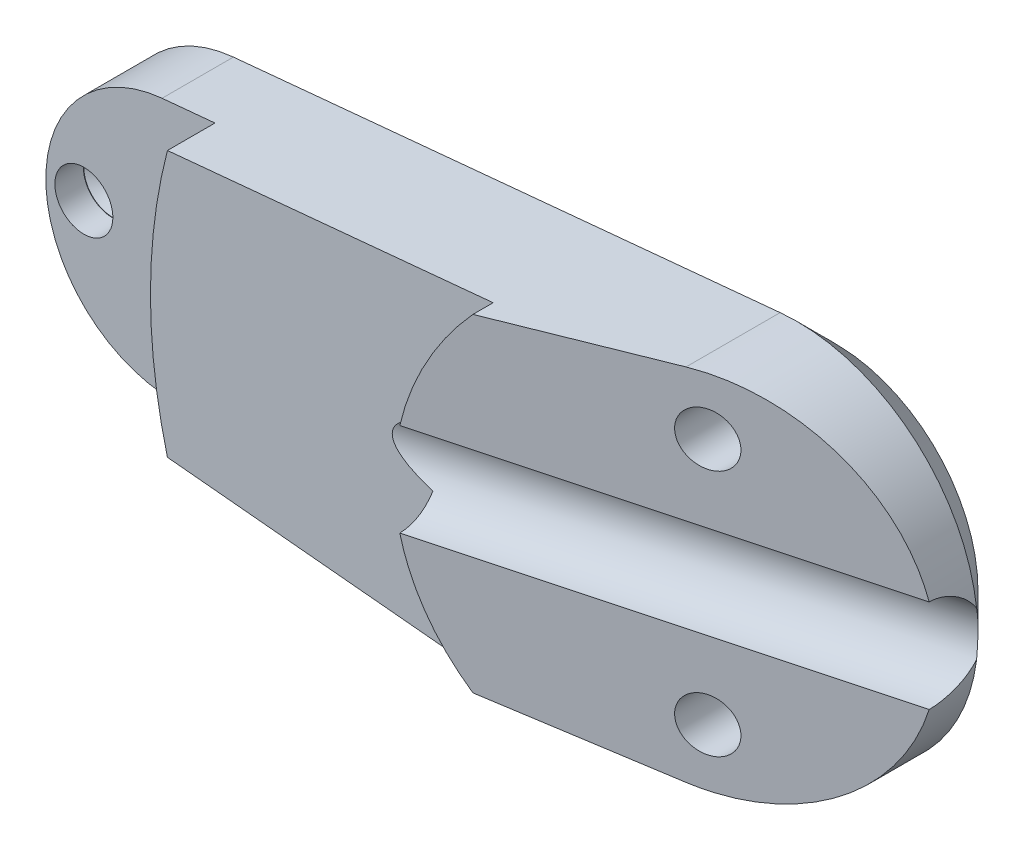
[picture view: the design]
ISO-10303-21;
HEADER;
FILE_DESCRIPTION(('STEP AP214'),'2;1');
FILE_NAME('part.step','',(''),(''),'','','');
FILE_SCHEMA(('AUTOMOTIVE_DESIGN { 1 0 10303 214 1 1 1 1 }'));
ENDSEC;
DATA;
#1=APPLICATION_CONTEXT('core data for automotive mechanical design processes');
#2=APPLICATION_PROTOCOL_DEFINITION('international standard','automotive_design',2000,#1);
#3=PRODUCT_CONTEXT('',#1,'mechanical');
#4=PRODUCT('Part','Part','',(#3));
#5=PRODUCT_RELATED_PRODUCT_CATEGORY('part','',(#4));
#6=PRODUCT_DEFINITION_FORMATION('','',#4);
#7=PRODUCT_DEFINITION_CONTEXT('part definition',#1,'design');
#8=PRODUCT_DEFINITION('design','',#6,#7);
#9=PRODUCT_DEFINITION_SHAPE('','',#8);
#10=(LENGTH_UNIT() NAMED_UNIT(*) SI_UNIT(.MILLI.,.METRE.));
#11=(NAMED_UNIT(*) PLANE_ANGLE_UNIT() SI_UNIT($,.RADIAN.));
#12=(NAMED_UNIT(*) SI_UNIT($,.STERADIAN.) SOLID_ANGLE_UNIT());
#13=UNCERTAINTY_MEASURE_WITH_UNIT(LENGTH_MEASURE(1.E-05),#10,'distance_accuracy_value','');
#14=(GEOMETRIC_REPRESENTATION_CONTEXT(3) GLOBAL_UNCERTAINTY_ASSIGNED_CONTEXT((#13)) GLOBAL_UNIT_ASSIGNED_CONTEXT((#10,
#11,#12)) REPRESENTATION_CONTEXT('',''));
#15=CARTESIAN_POINT('',(0.,0.,0.));
#16=DIRECTION('',(0.,0.,1.));
#17=DIRECTION('',(1.,0.,0.));
#18=AXIS2_PLACEMENT_3D('',#15,#16,#17);
#19=CARTESIAN_POINT('',(-19.,-25.,18.5));
#20=DIRECTION('',(-0.258819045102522,0.,-0.965925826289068));
#21=DIRECTION('',(-0.965925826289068,0.,0.258819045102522));
#22=AXIS2_PLACEMENT_3D('',#19,#20,#21);
#23=PLANE('',#22);
#24=CARTESIAN_POINT('',(0.,-13.,13.4089653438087));
#25=DIRECTION('',(-0.258819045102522,0.,-0.965925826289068));
#26=DIRECTION('',(0.965925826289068,0.,-0.258819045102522));
#27=AXIS2_PLACEMENT_3D('',#24,#25,#26);
#28=ELLIPSE('',#27,2.84700949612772,2.74999999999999);
#29=CARTESIAN_POINT('',(2.74999999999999,-13.,12.6721050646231));
#30=VERTEX_POINT('',#29);
#31=EDGE_CURVE('E214',#30,#30,#28,.T.);
#32=ORIENTED_EDGE('',*,*,#31,.T.);
#33=EDGE_LOOP('',(#32));
#34=FACE_BOUND('',#33,.T.);
#35=DIRECTION('',(-0.965925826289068,0.,0.258819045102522));
#36=VECTOR('',#35,1.);
#37=CARTESIAN_POINT('',(-66.9752612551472,-4.89897948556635,31.3549325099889));
#38=LINE('',#37,#36);
#39=CARTESIAN_POINT('',(-25.5342906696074,-4.89897948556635,20.2508579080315));
#40=VERTEX_POINT('',#39);
#41=CARTESIAN_POINT('',(18.3575597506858,-4.89897948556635,8.49007203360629));
#42=VERTEX_POINT('',#41);
#43=EDGE_CURVE('E230',#40,#42,#38,.F.);
#44=ORIENTED_EDGE('',*,*,#43,.F.);
#45=CARTESIAN_POINT('',(0.,0.,13.4089653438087));
#46=DIRECTION('',(-0.258819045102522,0.,-0.965925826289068));
#47=DIRECTION('',(0.965925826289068,0.,-0.258819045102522));
#48=AXIS2_PLACEMENT_3D('',#45,#46,#47);
#49=ELLIPSE('',#48,26.9171806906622,26.);
#50=CARTESIAN_POINT('',(-19.4699847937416,-17.231357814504,18.625932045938));
#51=VERTEX_POINT('',#50);
#52=EDGE_CURVE('E186',#40,#51,#49,.F.);
#53=ORIENTED_EDGE('',*,*,#52,.T.);
#54=DIRECTION('',(0.961862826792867,-0.0916240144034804,-0.257730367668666));
#55=VECTOR('',#54,1.);
#56=CARTESIAN_POINT('',(-10.7530083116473,-18.0617094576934,16.2902252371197));
#57=LINE('',#56,#55);
#58=CARTESIAN_POINT('',(-1.80172413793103,-18.9143805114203,13.8917358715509));
#59=VERTEX_POINT('',#58);
#60=EDGE_CURVE('E225',#51,#59,#57,.T.);
#61=ORIENTED_EDGE('',*,*,#60,.T.);
#62=CARTESIAN_POINT('',(0.,0.,13.4089653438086));
#63=DIRECTION('',(-0.258819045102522,0.,-0.965925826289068));
#64=DIRECTION('',(0.965925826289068,0.,-0.258819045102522));
#65=AXIS2_PLACEMENT_3D('',#62,#63,#64);
#66=ELLIPSE('',#65,19.6702474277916,19.);
#67=EDGE_CURVE('E375',#42,#59,#66,.T.);
#68=ORIENTED_EDGE('',*,*,#67,.F.);
#69=EDGE_LOOP('',(#44,#53,#61,#68));
#70=FACE_BOUND('',#69,.T.);
#71=ADVANCED_FACE('F38',(#34,#70),#23,.F.);
#72=CARTESIAN_POINT('',(0.,0.,18.5));
#73=DIRECTION('',(0.,0.,-1.));
#74=DIRECTION('',(-1.,0.,0.));
#75=AXIS2_PLACEMENT_3D('',#72,#73,#74);
#76=CYLINDRICAL_SURFACE('',#75,19.);
#77=DIRECTION('',(0.,0.,-1.));
#78=VECTOR('',#77,1.);
#79=CARTESIAN_POINT('',(-1.80172413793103,-18.9143805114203,50.));
#80=LINE('',#79,#78);
#81=CARTESIAN_POINT('',(-1.80172413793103,-18.9143805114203,4.));
#82=VERTEX_POINT('',#81);
#83=EDGE_CURVE('E240',#59,#82,#80,.T.);
#84=ORIENTED_EDGE('',*,*,#83,.T.);
#85=CARTESIAN_POINT('',(0.,0.,4.));
#86=DIRECTION('',(0.,0.,1.));
#87=DIRECTION('',(1.,0.,0.));
#88=AXIS2_PLACEMENT_3D('',#85,#86,#87);
#89=CIRCLE('',#88,19.);
#90=CARTESIAN_POINT('',(18.8560184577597,-2.33464513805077,3.99999999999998));
#91=VERTEX_POINT('',#90);
#92=EDGE_CURVE('E267',#82,#91,#89,.T.);
#93=ORIENTED_EDGE('',*,*,#92,.T.);
#94=CARTESIAN_POINT('',(19.,0.,13.4943115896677));
#95=CARTESIAN_POINT('',(18.9999933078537,-0.275202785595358,13.4943010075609));
#96=CARTESIAN_POINT('',(18.9939621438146,-0.550519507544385,13.4718550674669));
#97=CARTESIAN_POINT('',(18.9704599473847,-1.09345599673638,13.3825276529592));
#98=CARTESIAN_POINT('',(18.9529820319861,-1.36107103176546,13.3156194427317));
#99=CARTESIAN_POINT('',(18.9084732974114,-1.8808728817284,13.1388946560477));
#100=CARTESIAN_POINT('',(18.8814438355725,-2.13306188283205,13.0290841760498));
#101=CARTESIAN_POINT('',(18.820780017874,-2.6148130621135,12.7691257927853));
#102=CARTESIAN_POINT('',(18.7871464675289,-2.84437799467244,12.618982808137));
#103=CARTESIAN_POINT('',(18.717105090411,-3.27371933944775,12.2824751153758));
#104=CARTESIAN_POINT('',(18.6807051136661,-3.47357561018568,12.0962107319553));
#105=CARTESIAN_POINT('',(18.6091595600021,-3.8384687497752,11.6920348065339));
#106=CARTESIAN_POINT('',(18.5740138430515,-4.0035095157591,11.4741268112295));
#107=CARTESIAN_POINT('',(18.5093664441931,-4.29244776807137,11.0154345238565));
#108=CARTESIAN_POINT('',(18.4798034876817,-4.41680442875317,10.7749480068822));
#109=CARTESIAN_POINT('',(18.4290663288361,-4.62395487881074,10.275907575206));
#110=CARTESIAN_POINT('',(18.4078915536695,-4.70675150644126,10.0173548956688));
#111=CARTESIAN_POINT('',(18.3761291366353,-4.82927605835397,9.4903227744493));
#112=CARTESIAN_POINT('',(18.3655162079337,-4.8691068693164,9.22186864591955));
#113=CARTESIAN_POINT('',(18.3556109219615,-4.90631242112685,8.68186067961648));
#114=CARTESIAN_POINT('',(18.3563206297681,-4.90367941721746,8.41030628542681));
#115=CARTESIAN_POINT('',(18.368851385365,-4.85653271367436,7.86083197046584));
#116=CARTESIAN_POINT('',(18.3810907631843,-4.81044219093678,7.58305859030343));
#117=CARTESIAN_POINT('',(18.4156182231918,-4.67650714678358,7.03840657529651));
#118=CARTESIAN_POINT('',(18.4379098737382,-4.58864779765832,6.77153184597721));
#119=CARTESIAN_POINT('',(18.4917817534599,-4.36668197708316,6.23751517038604));
#120=CARTESIAN_POINT('',(18.5238833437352,-4.22987630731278,5.97154822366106));
#121=CARTESIAN_POINT('',(18.5929983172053,-3.91488247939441,5.46570565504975));
#122=CARTESIAN_POINT('',(18.6300136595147,-3.73667779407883,5.22584050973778));
#123=CARTESIAN_POINT('',(18.6865547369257,-3.43850177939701,4.88816551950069));
#124=CARTESIAN_POINT('',(18.7058458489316,-3.33226862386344,4.77793108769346));
#125=CARTESIAN_POINT('',(18.7440136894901,-3.11040322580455,4.56731840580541));
#126=CARTESIAN_POINT('',(18.7628906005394,-2.99477523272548,4.46693574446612));
#127=CARTESIAN_POINT('',(18.7996332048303,-2.75472956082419,4.27704838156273));
#128=CARTESIAN_POINT('',(18.8174987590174,-2.63031067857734,4.18754517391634));
#129=CARTESIAN_POINT('',(18.8516077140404,-2.37352960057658,4.02054472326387));
#130=CARTESIAN_POINT('',(18.8678520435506,-2.24117202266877,3.94304059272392));
#131=CARTESIAN_POINT('',(18.8971096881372,-1.97875140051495,3.80593436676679));
#132=CARTESIAN_POINT('',(18.910268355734,-1.84915620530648,3.74546783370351));
#133=CARTESIAN_POINT('',(18.9342523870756,-1.58482832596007,3.63666402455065));
#134=CARTESIAN_POINT('',(18.9450790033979,-1.45009844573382,3.58832023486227));
#135=CARTESIAN_POINT('',(18.9640292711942,-1.17659337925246,3.50446920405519));
#136=CARTESIAN_POINT('',(18.9721544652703,-1.03782055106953,3.46895463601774));
#137=CARTESIAN_POINT('',(18.985417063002,-0.757385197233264,3.41130367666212));
#138=CARTESIAN_POINT('',(18.9905548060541,-0.61572300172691,3.38916576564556));
#139=CARTESIAN_POINT('',(18.9972546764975,-0.346869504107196,3.36035807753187));
#140=CARTESIAN_POINT('',(18.9991537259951,-0.21984091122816,3.35222966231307));
#141=CARTESIAN_POINT('',(19.0003942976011,0.0345033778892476,3.34691602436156));
#142=CARTESIAN_POINT('',(18.9997349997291,0.161819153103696,3.34973431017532));
#143=CARTESIAN_POINT('',(18.9958773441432,0.415625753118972,3.36627922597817));
#144=CARTESIAN_POINT('',(18.9926804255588,0.54211700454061,3.37999967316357));
#145=CARTESIAN_POINT('',(18.9838427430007,0.793430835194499,3.4181573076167));
#146=CARTESIAN_POINT('',(18.9782010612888,0.918252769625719,3.44259851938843));
#147=CARTESIAN_POINT('',(18.9649136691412,1.16022512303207,3.50066493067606));
#148=CARTESIAN_POINT('',(18.9573592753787,1.27748059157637,3.53387400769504));
#149=CARTESIAN_POINT('',(18.9403485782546,1.50886817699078,3.60946805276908));
#150=CARTESIAN_POINT('',(18.9308916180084,1.62299919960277,3.65185619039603));
#151=CARTESIAN_POINT('',(18.9000118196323,1.959635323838,3.79211962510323));
#152=CARTESIAN_POINT('',(18.8760691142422,2.17657253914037,3.90314009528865));
#153=CARTESIAN_POINT('',(18.8220315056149,2.60395061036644,4.16395452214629));
#154=CARTESIAN_POINT('',(18.7916437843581,2.81311838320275,4.31575260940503));
#155=CARTESIAN_POINT('',(18.7286387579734,3.20588468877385,4.64908902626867));
#156=CARTESIAN_POINT('',(18.696020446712,3.38947156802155,4.83064082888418));
#157=CARTESIAN_POINT('',(18.6279094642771,3.74667698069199,5.23963098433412));
#158=CARTESIAN_POINT('',(18.5924888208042,3.91705384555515,5.46991060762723));
#159=CARTESIAN_POINT('',(18.5260873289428,4.21997907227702,5.95495437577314));
#160=CARTESIAN_POINT('',(18.4951085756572,4.35250961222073,6.20972998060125));
#161=CARTESIAN_POINT('',(18.4535368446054,4.52445867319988,6.61440421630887));
#162=CARTESIAN_POINT('',(18.4401634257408,4.57851585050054,6.75797295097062));
#163=CARTESIAN_POINT('',(18.4160636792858,4.67451195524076,7.04930585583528));
#164=CARTESIAN_POINT('',(18.4053363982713,4.71645524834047,7.1970684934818));
#165=CARTESIAN_POINT('',(18.3869047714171,4.78780641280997,7.49582532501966));
#166=CARTESIAN_POINT('',(18.3792014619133,4.81720998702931,7.64682060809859));
#167=CARTESIAN_POINT('',(18.3671268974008,4.86304580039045,7.95083811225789));
#168=CARTESIAN_POINT('',(18.3627540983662,4.87948405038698,8.10385936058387));
#169=CARTESIAN_POINT('',(18.3576011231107,4.89883443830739,8.40741806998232));
#170=CARTESIAN_POINT('',(18.3567436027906,4.9020377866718,8.55793558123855));
#171=CARTESIAN_POINT('',(18.358499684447,4.89545731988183,8.85860823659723));
#172=CARTESIAN_POINT('',(18.3611117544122,4.88567923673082,9.00876351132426));
#173=CARTESIAN_POINT('',(18.3697791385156,4.85298875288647,9.30751614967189));
#174=CARTESIAN_POINT('',(18.3758338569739,4.83007862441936,9.45611377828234));
#175=CARTESIAN_POINT('',(18.3912368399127,4.77109382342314,9.75049816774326));
#176=CARTESIAN_POINT('',(18.4005848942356,4.73501999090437,9.89628510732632));
#177=CARTESIAN_POINT('',(18.421558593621,4.65272514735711,10.1739856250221));
#178=CARTESIAN_POINT('',(18.4329862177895,4.6073606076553,10.3061686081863));
#179=CARTESIAN_POINT('',(18.4581479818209,4.50549939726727,10.5660035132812));
#180=CARTESIAN_POINT('',(18.4718829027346,4.44899895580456,10.693653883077));
#181=CARTESIAN_POINT('',(18.5012506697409,4.32524709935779,10.9433178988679));
#182=CARTESIAN_POINT('',(18.5168825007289,4.25800142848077,11.0653345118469));
#183=CARTESIAN_POINT('',(18.5495936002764,4.11316034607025,11.3029211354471));
#184=CARTESIAN_POINT('',(18.5666733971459,4.03556115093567,11.4184887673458));
#185=CARTESIAN_POINT('',(18.6011457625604,3.87349871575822,11.638323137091));
#186=CARTESIAN_POINT('',(18.6185060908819,3.78937379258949,11.7428446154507));
#187=CARTESIAN_POINT('',(18.6536173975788,3.61257261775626,11.9443834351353));
#188=CARTESIAN_POINT('',(18.671368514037,3.51989330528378,12.041398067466));
#189=CARTESIAN_POINT('',(18.7067592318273,3.32668001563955,12.2272313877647));
#190=CARTESIAN_POINT('',(18.7243988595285,3.22614797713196,12.3160520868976));
#191=CARTESIAN_POINT('',(18.7590933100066,3.01787434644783,12.4850032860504));
#192=CARTESIAN_POINT('',(18.7761479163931,2.91013012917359,12.5651305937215));
#193=CARTESIAN_POINT('',(18.8092893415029,2.68762892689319,12.716575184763));
#194=CARTESIAN_POINT('',(18.8253705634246,2.57283785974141,12.7878436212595));
#195=CARTESIAN_POINT('',(18.856035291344,2.33752392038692,12.9206775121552));
#196=CARTESIAN_POINT('',(18.8706182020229,2.21699879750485,12.9822391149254));
#197=CARTESIAN_POINT('',(18.8978740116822,1.97119842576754,13.0952219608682));
#198=CARTESIAN_POINT('',(18.9105485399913,1.84592734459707,13.1466518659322));
#199=CARTESIAN_POINT('',(18.9336679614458,1.59140845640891,13.2391533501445));
#200=CARTESIAN_POINT('',(18.9441123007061,1.46215967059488,13.2802223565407));
#201=CARTESIAN_POINT('',(18.9684813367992,1.11513261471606,13.3751079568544));
#202=CARTESIAN_POINT('',(18.9802308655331,0.894612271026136,13.4197595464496));
#203=CARTESIAN_POINT('',(18.995992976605,0.449419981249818,13.4793658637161));
#204=CARTESIAN_POINT('',(19.0000054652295,0.224747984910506,13.4943202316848));
#205=CARTESIAN_POINT('',(19.,0.,13.4943115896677));
#206=B_SPLINE_CURVE_WITH_KNOTS('',3,(#94,#95,#96,#97,#98,#99,#100,#101,#102,#103,#104,#105,#106,
#107,#108,#109,#110,#111,#112,#113,#114,#115,#116,#117,#118,#119,#120,#121,#122,#123,#124,#125,
#126,#127,#128,#129,#130,#131,#132,#133,#134,#135,#136,#137,#138,#139,#140,#141,#142,#143,#144,
#145,#146,#147,#148,#149,#150,#151,#152,#153,#154,#155,#156,#157,#158,#159,#160,#161,#162,#163,
#164,#165,#166,#167,#168,#169,#170,#171,#172,#173,#174,#175,#176,#177,#178,#179,#180,#181,#182,
#183,#184,#185,#186,#187,#188,#189,#190,#191,#192,#193,#194,#195,#196,#197,#198,#199,#200,#201,
#202,#203,#204,#205),.UNSPECIFIED.,.T.,.F.,(4,2,2,2,2,2,2,2,2,2,2,2,2,2,2,2,2,2,2,2,2,2,2,2,2,2,
2,2,2,2,2,2,2,2,2,2,2,2,2,2,2,2,2,2,2,2,2,2,2,2,2,2,2,2,2,4),(0.,0.8248328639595,
1.65016216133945,2.47537422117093,3.30048569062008,4.12333746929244,4.94609709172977,
5.75922181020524,6.57229099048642,7.38340882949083,8.1946746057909,9.03655747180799,
9.87873942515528,10.7772264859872,11.6760728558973,12.1384839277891,12.6006869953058,
13.0629534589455,13.5249535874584,13.9551911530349,14.3851970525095,14.8149569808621,
15.2446680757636,15.6260917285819,16.0076376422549,16.3889673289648,16.7704402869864,
17.1363242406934,17.5023347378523,18.2337776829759,19.011361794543,19.7892989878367,
20.6516247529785,21.514355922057,21.9758593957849,22.4371963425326,22.8986912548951,
23.3599720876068,23.8110473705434,24.2619235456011,24.7127217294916,25.1634911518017,
25.5836185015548,26.0038883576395,26.4239342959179,26.8441341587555,27.249524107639,
27.6550596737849,28.0604954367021,28.4660795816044,28.8738092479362,29.2817002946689,
29.6892410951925,30.0968829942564,30.7704854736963,31.4440961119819),.UNSPECIFIED.);
#207=EDGE_CURVE('E233',#42,#91,#206,.T.);
#208=ORIENTED_EDGE('',*,*,#207,.F.);
#209=ORIENTED_EDGE('',*,*,#67,.T.);
#210=EDGE_LOOP('',(#84,#93,#208,#209));
#211=FACE_BOUND('',#210,.T.);
#212=ADVANCED_FACE('F334',(#211),#76,.T.);
#213=CARTESIAN_POINT('',(18.8560184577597,2.33464513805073,4.00000000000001));
#214=VERTEX_POINT('',#213);
#215=CARTESIAN_POINT('',(18.3575597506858,4.89897948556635,8.49007203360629));
#216=VERTEX_POINT('',#215);
#217=EDGE_CURVE('E232',#214,#216,#206,.T.);
#218=ORIENTED_EDGE('',*,*,#217,.F.);
#219=CARTESIAN_POINT('',(0.,0.,4.));
#220=DIRECTION('',(0.,0.,1.));
#221=DIRECTION('',(1.,0.,0.));
#222=AXIS2_PLACEMENT_3D('',#219,#220,#221);
#223=CIRCLE('',#222,19.);
#224=CARTESIAN_POINT('',(-1.80172413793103,18.9143805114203,4.));
#225=VERTEX_POINT('',#224);
#226=EDGE_CURVE('E398',#214,#225,#223,.T.);
#227=ORIENTED_EDGE('',*,*,#226,.T.);
#228=DIRECTION('',(0.,0.,-1.));
#229=VECTOR('',#228,1.);
#230=CARTESIAN_POINT('',(-1.80172413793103,18.9143805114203,50.));
#231=LINE('',#230,#229);
#232=CARTESIAN_POINT('',(-1.80172413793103,18.9143805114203,13.8917358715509));
#233=VERTEX_POINT('',#232);
#234=EDGE_CURVE('E241',#233,#225,#231,.T.);
#235=ORIENTED_EDGE('',*,*,#234,.F.);
#236=EDGE_CURVE('E358',#233,#216,#66,.T.);
#237=ORIENTED_EDGE('',*,*,#236,.T.);
#238=EDGE_LOOP('',(#218,#227,#235,#237));
#239=FACE_BOUND('',#238,.T.);
#240=ADVANCED_FACE('F40',(#239),#76,.T.);
#241=CARTESIAN_POINT('',(0.,13.,13.4089653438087));
#242=DIRECTION('',(-0.258819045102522,0.,-0.965925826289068));
#243=DIRECTION('',(0.965925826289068,0.,-0.258819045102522));
#244=AXIS2_PLACEMENT_3D('',#241,#242,#243);
#245=ELLIPSE('',#244,2.84700949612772,2.74999999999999);
#246=CARTESIAN_POINT('',(2.74999999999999,13.,12.6721050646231));
#247=VERTEX_POINT('',#246);
#248=EDGE_CURVE('E219',#247,#247,#245,.T.);
#249=ORIENTED_EDGE('',*,*,#248,.T.);
#250=EDGE_LOOP('',(#249));
#251=FACE_BOUND('',#250,.T.);
#252=DIRECTION('',(-0.961862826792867,-0.0916240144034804,0.257730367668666));
#253=VECTOR('',#252,1.);
#254=CARTESIAN_POINT('',(-10.7530083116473,18.0617094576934,16.2902252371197));
#255=LINE('',#254,#253);
#256=CARTESIAN_POINT('',(-19.4699847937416,17.231357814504,18.625932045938));
#257=VERTEX_POINT('',#256);
#258=EDGE_CURVE('E222',#233,#257,#255,.T.);
#259=ORIENTED_EDGE('',*,*,#258,.T.);
#260=CARTESIAN_POINT('',(-25.5342906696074,4.89897948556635,20.2508579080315));
#261=VERTEX_POINT('',#260);
#262=EDGE_CURVE('E182',#257,#261,#49,.F.);
#263=ORIENTED_EDGE('',*,*,#262,.T.);
#264=DIRECTION('',(-0.965925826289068,0.,0.258819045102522));
#265=VECTOR('',#264,1.);
#266=CARTESIAN_POINT('',(-66.9752612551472,4.89897948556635,31.3549325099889));
#267=LINE('',#266,#265);
#268=EDGE_CURVE('E227',#216,#261,#267,.T.);
#269=ORIENTED_EDGE('',*,*,#268,.F.);
#270=ORIENTED_EDGE('',*,*,#236,.F.);
#271=EDGE_LOOP('',(#259,#263,#269,#270));
#272=FACE_BOUND('',#271,.T.);
#273=ADVANCED_FACE('F337',(#251,#272),#23,.F.);
#274=CARTESIAN_POINT('',(0.,0.,0.));
#275=DIRECTION('',(0.,0.,1.));
#276=DIRECTION('',(1.,0.,0.));
#277=AXIS2_PLACEMENT_3D('',#274,#275,#276);
#278=PLANE('',#277);
#279=CARTESIAN_POINT('',(0.,13.,0.));
#280=DIRECTION('',(0.,0.,-1.));
#281=DIRECTION('',(-1.,0.,0.));
#282=AXIS2_PLACEMENT_3D('',#279,#280,#281);
#283=CIRCLE('',#282,2.75);
#284=CARTESIAN_POINT('',(2.02282046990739,14.8629807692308,0.));
#285=VERTEX_POINT('',#284);
#286=CARTESIAN_POINT('',(-2.01038090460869,14.8763977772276,0.));
#287=VERTEX_POINT('',#286);
#288=EDGE_CURVE('E217',#285,#287,#283,.T.);
#289=ORIENTED_EDGE('',*,*,#288,.F.);
#290=CARTESIAN_POINT('',(0.,0.,0.));
#291=DIRECTION('',(0.,0.,1.));
#292=DIRECTION('',(1.,0.,0.));
#293=AXIS2_PLACEMENT_3D('',#290,#291,#292);
#294=CIRCLE('',#293,15.);
#295=CARTESIAN_POINT('',(2.02282046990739,-14.8629807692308,0.));
#296=VERTEX_POINT('',#295);
#297=EDGE_CURVE('E402',#285,#296,#294,.F.);
#298=ORIENTED_EDGE('',*,*,#297,.T.);
#299=CARTESIAN_POINT('',(0.,-13.,0.));
#300=DIRECTION('',(0.,0.,-1.));
#301=DIRECTION('',(-1.,0.,0.));
#302=AXIS2_PLACEMENT_3D('',#299,#300,#301);
#303=CIRCLE('',#302,2.75);
#304=CARTESIAN_POINT('',(-2.01038090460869,-14.8763977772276,0.));
#305=VERTEX_POINT('',#304);
#306=EDGE_CURVE('E211',#305,#296,#303,.T.);
#307=ORIENTED_EDGE('',*,*,#306,.F.);
#308=DIRECTION('',(-0.995493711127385,0.0948275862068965,0.));
#309=VECTOR('',#308,1.);
#310=CARTESIAN_POINT('',(-58.9008620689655,-9.45719025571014,0.));
#311=LINE('',#310,#309);
#312=CARTESIAN_POINT('',(-58.9008620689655,-9.45719025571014,0.));
#313=VERTEX_POINT('',#312);
#314=EDGE_CURVE('E406',#305,#313,#311,.T.);
#315=ORIENTED_EDGE('',*,*,#314,.T.);
#316=CARTESIAN_POINT('',(-58.,0.,0.));
#317=DIRECTION('',(0.,0.,1.));
#318=DIRECTION('',(1.,0.,0.));
#319=AXIS2_PLACEMENT_3D('',#316,#317,#318);
#320=CIRCLE('',#319,9.49999999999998);
#321=CARTESIAN_POINT('',(-58.9008620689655,9.45719025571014,0.));
#322=VERTEX_POINT('',#321);
#323=EDGE_CURVE('E408',#313,#322,#320,.F.);
#324=ORIENTED_EDGE('',*,*,#323,.T.);
#325=DIRECTION('',(0.995493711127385,0.0948275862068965,0.));
#326=VECTOR('',#325,1.);
#327=CARTESIAN_POINT('',(-1.42241379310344,14.9324056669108,0.));
#328=LINE('',#327,#326);
#329=EDGE_CURVE('E395',#322,#287,#328,.T.);
#330=ORIENTED_EDGE('',*,*,#329,.T.);
#331=EDGE_LOOP('',(#289,#298,#307,#315,#324,#330));
#332=FACE_BOUND('',#331,.T.);
#333=ADVANCED_FACE('F345',(#332),#278,.F.);
#334=CARTESIAN_POINT('',(-1.80172413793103,18.9143805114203,50.));
#335=DIRECTION('',(-0.0948275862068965,0.995493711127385,0.));
#336=DIRECTION('',(-0.995493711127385,-0.0948275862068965,0.));
#337=AXIS2_PLACEMENT_3D('',#334,#335,#336);
#338=PLANE('',#337);
#339=DIRECTION('',(-0.995493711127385,-0.0948275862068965,0.));
#340=VECTOR('',#339,1.);
#341=CARTESIAN_POINT('',(-1.80172413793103,18.9143805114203,11.5));
#342=LINE('',#341,#340);
#343=CARTESIAN_POINT('',(-53.7131657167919,13.9694605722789,11.5));
#344=VERTEX_POINT('',#343);
#345=CARTESIAN_POINT('',(-59.2801724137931,13.4391651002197,11.5));
#346=VERTEX_POINT('',#345);
#347=EDGE_CURVE('E198',#344,#346,#342,.T.);
#348=ORIENTED_EDGE('',*,*,#347,.F.);
#349=DIRECTION('',(0.,0.,-1.));
#350=VECTOR('',#349,1.);
#351=CARTESIAN_POINT('',(-53.7131657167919,13.9694605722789,0.));
#352=LINE('',#351,#350);
#353=CARTESIAN_POINT('',(-53.7131657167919,13.9694605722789,16.5));
#354=VERTEX_POINT('',#353);
#355=EDGE_CURVE('E194',#354,#344,#352,.T.);
#356=ORIENTED_EDGE('',*,*,#355,.F.);
#357=DIRECTION('',(-0.995493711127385,-0.0948275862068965,0.));
#358=VECTOR('',#357,1.);
#359=CARTESIAN_POINT('',(-1.80172413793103,18.9143805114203,16.5));
#360=LINE('',#359,#358);
#361=CARTESIAN_POINT('',(-19.4699847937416,17.231357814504,16.5));
#362=VERTEX_POINT('',#361);
#363=EDGE_CURVE('E192',#362,#354,#360,.T.);
#364=ORIENTED_EDGE('',*,*,#363,.F.);
#365=DIRECTION('',(0.,0.,-1.));
#366=VECTOR('',#365,1.);
#367=CARTESIAN_POINT('',(-19.4699847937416,17.231357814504,0.));
#368=LINE('',#367,#366);
#369=EDGE_CURVE('E185',#257,#362,#368,.T.);
#370=ORIENTED_EDGE('',*,*,#369,.F.);
#371=ORIENTED_EDGE('',*,*,#258,.F.);
#372=ORIENTED_EDGE('',*,*,#234,.T.);
#373=DIRECTION('',(-0.995493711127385,-0.0948275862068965,0.));
#374=VECTOR('',#373,1.);
#375=CARTESIAN_POINT('',(-59.2801724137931,13.4391651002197,4.));
#376=LINE('',#375,#374);
#377=CARTESIAN_POINT('',(-59.2801724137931,13.4391651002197,4.));
#378=VERTEX_POINT('',#377);
#379=EDGE_CURVE('E295',#225,#378,#376,.T.);
#380=ORIENTED_EDGE('',*,*,#379,.T.);
#381=DIRECTION('',(0.,0.,-1.));
#382=VECTOR('',#381,1.);
#383=CARTESIAN_POINT('',(-59.2801724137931,13.4391651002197,50.));
#384=LINE('',#383,#382);
#385=EDGE_CURVE('E382',#346,#378,#384,.T.);
#386=ORIENTED_EDGE('',*,*,#385,.F.);
#387=EDGE_LOOP('',(#348,#356,#364,#370,#371,#372,#380,#386));
#388=FACE_BOUND('',#387,.T.);
#389=ADVANCED_FACE('F253',(#388),#338,.T.);
#390=CARTESIAN_POINT('',(-58.,0.,50.));
#391=DIRECTION('',(0.,0.,-1.));
#392=DIRECTION('',(-1.,0.,0.));
#393=AXIS2_PLACEMENT_3D('',#390,#391,#392);
#394=CYLINDRICAL_SURFACE('',#393,13.5);
#395=DIRECTION('',(0.,0.,-1.));
#396=VECTOR('',#395,1.);
#397=CARTESIAN_POINT('',(-59.2801724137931,-13.4391651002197,50.));
#398=LINE('',#397,#396);
#399=CARTESIAN_POINT('',(-59.2801724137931,-13.4391651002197,11.5));
#400=VERTEX_POINT('',#399);
#401=CARTESIAN_POINT('',(-59.2801724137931,-13.4391651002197,4.));
#402=VERTEX_POINT('',#401);
#403=EDGE_CURVE('E381',#400,#402,#398,.T.);
#404=ORIENTED_EDGE('',*,*,#403,.F.);
#405=CARTESIAN_POINT('',(-58.,0.,11.5));
#406=DIRECTION('',(0.,0.,-1.));
#407=DIRECTION('',(-1.,0.,0.));
#408=AXIS2_PLACEMENT_3D('',#405,#406,#407);
#409=CIRCLE('',#408,13.5);
#410=EDGE_CURVE('E196',#346,#400,#409,.F.);
#411=ORIENTED_EDGE('',*,*,#410,.F.);
#412=ORIENTED_EDGE('',*,*,#385,.T.);
#413=CARTESIAN_POINT('',(-58.,0.,4.));
#414=DIRECTION('',(0.,0.,1.));
#415=DIRECTION('',(1.,0.,0.));
#416=AXIS2_PLACEMENT_3D('',#413,#414,#415);
#417=CIRCLE('',#416,13.5);
#418=EDGE_CURVE('E390',#378,#402,#417,.T.);
#419=ORIENTED_EDGE('',*,*,#418,.T.);
#420=EDGE_LOOP('',(#404,#411,#412,#419));
#421=FACE_BOUND('',#420,.T.);
#422=ADVANCED_FACE('F388',(#421),#394,.T.);
#423=CARTESIAN_POINT('',(-1.80172413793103,-18.9143805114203,50.));
#424=DIRECTION('',(-0.0948275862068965,-0.995493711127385,0.));
#425=DIRECTION('',(0.995493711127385,-0.0948275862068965,0.));
#426=AXIS2_PLACEMENT_3D('',#423,#424,#425);
#427=PLANE('',#426);
#428=DIRECTION('',(0.995493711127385,-0.0948275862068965,0.));
#429=VECTOR('',#428,1.);
#430=CARTESIAN_POINT('',(-1.80172413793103,-18.9143805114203,11.5));
#431=LINE('',#430,#429);
#432=CARTESIAN_POINT('',(-53.7131657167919,-13.9694605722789,11.5));
#433=VERTEX_POINT('',#432);
#434=EDGE_CURVE('E11',#400,#433,#431,.T.);
#435=ORIENTED_EDGE('',*,*,#434,.F.);
#436=ORIENTED_EDGE('',*,*,#403,.T.);
#437=DIRECTION('',(0.995493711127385,-0.0948275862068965,0.));
#438=VECTOR('',#437,1.);
#439=CARTESIAN_POINT('',(-1.80172413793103,-18.9143805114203,4.));
#440=LINE('',#439,#438);
#441=EDGE_CURVE('E399',#402,#82,#440,.T.);
#442=ORIENTED_EDGE('',*,*,#441,.T.);
#443=ORIENTED_EDGE('',*,*,#83,.F.);
#444=ORIENTED_EDGE('',*,*,#60,.F.);
#445=DIRECTION('',(0.,0.,-1.));
#446=VECTOR('',#445,1.);
#447=CARTESIAN_POINT('',(-19.4699847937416,-17.231357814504,0.));
#448=LINE('',#447,#446);
#449=CARTESIAN_POINT('',(-19.4699847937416,-17.231357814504,16.5));
#450=VERTEX_POINT('',#449);
#451=EDGE_CURVE('E188',#450,#51,#448,.F.);
#452=ORIENTED_EDGE('',*,*,#451,.F.);
#453=DIRECTION('',(0.995493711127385,-0.0948275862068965,0.));
#454=VECTOR('',#453,1.);
#455=CARTESIAN_POINT('',(-1.80172413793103,-18.9143805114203,16.5));
#456=LINE('',#455,#454);
#457=CARTESIAN_POINT('',(-53.7131657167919,-13.9694605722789,16.5));
#458=VERTEX_POINT('',#457);
#459=EDGE_CURVE('E190',#458,#450,#456,.T.);
#460=ORIENTED_EDGE('',*,*,#459,.F.);
#461=DIRECTION('',(0.,0.,-1.));
#462=VECTOR('',#461,1.);
#463=CARTESIAN_POINT('',(-53.7131657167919,-13.9694605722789,0.));
#464=LINE('',#463,#462);
#465=EDGE_CURVE('E47',#433,#458,#464,.F.);
#466=ORIENTED_EDGE('',*,*,#465,.F.);
#467=EDGE_LOOP('',(#435,#436,#442,#443,#444,#452,#460,#466));
#468=FACE_BOUND('',#467,.T.);
#469=ADVANCED_FACE('F249',(#468),#427,.T.);
#470=CARTESIAN_POINT('',(-66.9493793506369,0.,31.4515250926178));
#471=DIRECTION('',(-0.965925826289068,0.,0.258819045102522));
#472=DIRECTION('',(0.258819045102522,0.,0.965925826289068));
#473=AXIS2_PLACEMENT_3D('',#470,#471,#472);
#474=CYLINDRICAL_SURFACE('',#473,4.89999999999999);
#475=CARTESIAN_POINT('',(-26.,0.,25.5520252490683));
#476=CARTESIAN_POINT('',(-26.000001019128,-0.129255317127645,25.5520282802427));
#477=CARTESIAN_POINT('',(-25.999034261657,-0.258481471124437,25.5464686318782));
#478=CARTESIAN_POINT('',(-25.9951979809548,-0.515994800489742,25.5243045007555));
#479=CARTESIAN_POINT('',(-25.9923280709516,-0.64428177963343,25.5076977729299));
#480=CARTESIAN_POINT('',(-25.9847657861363,-0.898998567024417,25.4636226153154));
#481=CARTESIAN_POINT('',(-25.9800722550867,-1.02542714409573,25.4361472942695));
#482=CARTESIAN_POINT('',(-25.9689966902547,-1.27549347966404,25.3706497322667));
#483=CARTESIAN_POINT('',(-25.962614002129,-1.39913013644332,25.3326234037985));
#484=CARTESIAN_POINT('',(-25.9483618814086,-1.64234697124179,25.2465862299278));
#485=CARTESIAN_POINT('',(-25.9404972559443,-1.76193883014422,25.1986076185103));
#486=CARTESIAN_POINT('',(-25.9234809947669,-1.99675243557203,25.0930959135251));
#487=CARTESIAN_POINT('',(-25.9143288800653,-2.11197253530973,25.0355592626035));
#488=CARTESIAN_POINT('',(-25.8852990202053,-2.44995348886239,24.8494627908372));
#489=CARTESIAN_POINT('',(-25.8638330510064,-2.66527364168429,24.7073309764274));
#490=CARTESIAN_POINT('',(-25.8177411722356,-3.08059354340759,24.3845811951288));
#491=CARTESIAN_POINT('',(-25.7930150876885,-3.27942579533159,24.2024884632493));
#492=CARTESIAN_POINT('',(-25.7436858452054,-3.64650063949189,23.8096619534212));
#493=CARTESIAN_POINT('',(-25.7190827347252,-3.81473219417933,23.5989178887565));
#494=CARTESIAN_POINT('',(-25.6704165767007,-4.13004800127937,23.1359213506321));
#495=CARTESIAN_POINT('',(-25.646564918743,-4.27424917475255,22.8816797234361));
#496=CARTESIAN_POINT('',(-25.6043895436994,-4.5200482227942,22.3528941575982));
#497=CARTESIAN_POINT('',(-25.5860674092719,-4.62163390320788,22.0783444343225));
#498=CARTESIAN_POINT('',(-25.556556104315,-4.78219906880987,21.5058319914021));
#499=CARTESIAN_POINT('',(-25.5456491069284,-4.83950338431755,21.2073815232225));
#500=CARTESIAN_POINT('',(-25.5336050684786,-4.90266233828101,20.6048638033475));
#501=CARTESIAN_POINT('',(-25.5324664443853,-4.90852531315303,20.3007974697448));
#502=CARTESIAN_POINT('',(-25.5402604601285,-4.86780160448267,19.7042661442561));
#503=CARTESIAN_POINT('',(-25.5489306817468,-4.82258160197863,19.4117056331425));
#504=CARTESIAN_POINT('',(-25.5750772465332,-4.68193381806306,18.8393213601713));
#505=CARTESIAN_POINT('',(-25.5925510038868,-4.58652077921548,18.5594938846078));
#506=CARTESIAN_POINT('',(-25.6332498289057,-4.35313096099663,18.0344368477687));
#507=CARTESIAN_POINT('',(-25.6561662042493,-4.21736391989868,17.7881995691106));
#508=CARTESIAN_POINT('',(-25.7054792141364,-3.90552842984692,17.3231192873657));
#509=CARTESIAN_POINT('',(-25.731875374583,-3.72946546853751,17.1042725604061));
#510=CARTESIAN_POINT('',(-25.7843835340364,-3.34691049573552,16.7055441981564));
#511=CARTESIAN_POINT('',(-25.8104861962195,-3.14128709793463,16.5248267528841));
#512=CARTESIAN_POINT('',(-25.8601290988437,-2.70230041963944,16.2005571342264));
#513=CARTESIAN_POINT('',(-25.8836693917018,-2.4689377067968,16.0570042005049));
#514=CARTESIAN_POINT('',(-25.9255244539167,-1.98161659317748,15.8110862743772));
#515=CARTESIAN_POINT('',(-25.9438497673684,-1.72770110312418,15.7086379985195));
#516=CARTESIAN_POINT('',(-25.9733262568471,-1.20603945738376,15.5470905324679));
#517=CARTESIAN_POINT('',(-25.9844773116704,-0.938293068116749,15.4879920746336));
#518=CARTESIAN_POINT('',(-25.9984126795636,-0.395554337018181,15.4144749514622));
#519=CARTESIAN_POINT('',(-26.0011672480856,-0.120539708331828,15.4002151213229));
#520=CARTESIAN_POINT('',(-25.9979235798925,0.428034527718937,15.4171741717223));
#521=CARTESIAN_POINT('',(-25.9919252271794,0.701594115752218,15.4483936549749));
#522=CARTESIAN_POINT('',(-25.9718199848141,1.23984445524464,15.5556110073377));
#523=CARTESIAN_POINT('',(-25.9577029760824,1.50452370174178,15.6316647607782));
#524=CARTESIAN_POINT('',(-25.9229108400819,2.01711087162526,15.8266891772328));
#525=CARTESIAN_POINT('',(-25.9022357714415,2.2650189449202,15.9456594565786));
#526=CARTESIAN_POINT('',(-25.8566646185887,2.73660382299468,16.2232297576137));
#527=CARTESIAN_POINT('',(-25.8317752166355,2.96031808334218,16.3817672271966));
#528=CARTESIAN_POINT('',(-25.7805399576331,3.37757765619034,16.734322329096));
#529=CARTESIAN_POINT('',(-25.7541941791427,3.57112459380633,16.9283380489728));
#530=CARTESIAN_POINT('',(-25.7030981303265,3.92201012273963,17.3456951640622));
#531=CARTESIAN_POINT('',(-25.6783424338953,4.07947714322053,17.5689279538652));
#532=CARTESIAN_POINT('',(-25.6330597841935,4.35497616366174,18.0388892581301));
#533=CARTESIAN_POINT('',(-25.6125327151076,4.47300924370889,18.285617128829));
#534=CARTESIAN_POINT('',(-25.5778392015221,4.66733120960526,18.7963861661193));
#535=CARTESIAN_POINT('',(-25.5636954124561,4.7434716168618,19.0604852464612));
#536=CARTESIAN_POINT('',(-25.5432750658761,4.85223412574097,19.5977662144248));
#537=CARTESIAN_POINT('',(-25.536999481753,4.88485084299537,19.8709492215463));
#538=CARTESIAN_POINT('',(-25.5327388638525,4.9070757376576,20.4263264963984));
#539=CARTESIAN_POINT('',(-25.5349774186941,4.89552397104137,20.7085680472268));
#540=CARTESIAN_POINT('',(-25.5477942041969,4.82818125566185,21.2675328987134));
#541=CARTESIAN_POINT('',(-25.5583745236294,4.77237922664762,21.5442547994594));
#542=CARTESIAN_POINT('',(-25.5872552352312,4.61508950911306,22.0978754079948));
#543=CARTESIAN_POINT('',(-25.6058907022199,4.51160429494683,22.3741879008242));
#544=CARTESIAN_POINT('',(-25.6487356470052,4.26126739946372,22.9061999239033));
#545=CARTESIAN_POINT('',(-25.6729466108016,4.1144041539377,23.1618939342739));
#546=CARTESIAN_POINT('',(-25.7117225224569,3.86197040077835,23.5277418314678));
#547=CARTESIAN_POINT('',(-25.7252644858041,3.77096471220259,23.6482905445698));
#548=CARTESIAN_POINT('',(-25.7526833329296,3.5789256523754,23.8810527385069));
#549=CARTESIAN_POINT('',(-25.7665600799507,3.47789632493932,23.9932695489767));
#550=CARTESIAN_POINT('',(-25.794235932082,3.26630968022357,24.2084646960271));
#551=CARTESIAN_POINT('',(-25.8080349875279,3.15574687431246,24.3114376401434));
#552=CARTESIAN_POINT('',(-25.8351081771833,2.92584535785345,24.5070481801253));
#553=CARTESIAN_POINT('',(-25.8483825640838,2.80651095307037,24.5996907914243));
#554=CARTESIAN_POINT('',(-25.8735369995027,2.56406213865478,24.7706896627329));
#555=CARTESIAN_POINT('',(-25.8854494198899,2.44122186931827,24.8494296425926));
#556=CARTESIAN_POINT('',(-25.9080057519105,2.1888970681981,24.9955046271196));
#557=CARTESIAN_POINT('',(-25.9186502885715,2.05941585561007,25.062845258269));
#558=CARTESIAN_POINT('',(-25.9383123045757,1.79485848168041,25.1852670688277));
#559=CARTESIAN_POINT('',(-25.947331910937,1.65978992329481,25.2403642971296));
#560=CARTESIAN_POINT('',(-25.9634479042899,1.38503174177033,25.3376616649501));
#561=CARTESIAN_POINT('',(-25.9705449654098,1.24534375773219,25.3798663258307));
#562=CARTESIAN_POINT('',(-25.9842099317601,0.923739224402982,25.460510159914));
#563=CARTESIAN_POINT('',(-25.9901018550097,0.740725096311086,25.494760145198));
#564=CARTESIAN_POINT('',(-25.9979959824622,0.371787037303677,25.5405144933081));
#565=CARTESIAN_POINT('',(-25.9999985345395,0.185863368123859,25.5520208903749));
#566=CARTESIAN_POINT('',(-26.,0.,25.5520252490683));
#567=B_SPLINE_CURVE_WITH_KNOTS('',3,(#475,#476,#477,#478,#479,#480,#481,#482,#483,#484,#485,
#486,#487,#488,#489,#490,#491,#492,#493,#494,#495,#496,#497,#498,#499,#500,#501,#502,#503,#504,
#505,#506,#507,#508,#509,#510,#511,#512,#513,#514,#515,#516,#517,#518,#519,#520,#521,#522,#523,
#524,#525,#526,#527,#528,#529,#530,#531,#532,#533,#534,#535,#536,#537,#538,#539,#540,#541,#542,
#543,#544,#545,#546,#547,#548,#549,#550,#551,#552,#553,#554,#555,#556,#557,#558,#559,#560,#561,
#562,#563,#564,#565,#566),.UNSPECIFIED.,.T.,.F.,(4,2,2,2,2,2,2,2,2,2,2,2,2,2,2,2,2,2,2,2,2,2,2,
2,2,2,2,2,2,2,2,2,2,2,2,2,2,2,2,2,2,2,2,2,2,4),(0.,0.387593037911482,0.77526486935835,
1.16318290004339,1.55125142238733,1.93808214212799,2.32505715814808,3.0982543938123,
3.90717567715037,4.71638815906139,5.59225142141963,6.46836513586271,7.37618896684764,
8.28386567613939,9.16782175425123,10.0515183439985,10.8937073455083,11.735781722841,
12.5568504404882,13.3779023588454,14.1972822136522,15.0166759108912,15.8389689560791,
16.6612728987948,17.4846039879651,18.3079277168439,19.1299580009,19.9519439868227,
20.770956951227,21.589947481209,22.4118223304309,23.2337988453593,24.0775083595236,
24.9214292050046,25.8044632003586,26.6877328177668,27.1422162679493,27.5965171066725,
28.0510812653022,28.505423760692,28.9440275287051,29.382414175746,29.8202227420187,
30.2578775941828,30.8152689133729,31.372610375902),.UNSPECIFIED.);
#568=CARTESIAN_POINT('',(-25.8146605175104,-3.09891954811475,16.5));
#569=VERTEX_POINT('',#568);
#570=EDGE_CURVE('E304',#40,#569,#567,.T.);
#571=ORIENTED_EDGE('',*,*,#570,.F.);
#572=ORIENTED_EDGE('',*,*,#43,.T.);
#573=ORIENTED_EDGE('',*,*,#207,.T.);
#574=CARTESIAN_POINT('',(18.8560184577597,-2.33464513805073,4.));
#575=CARTESIAN_POINT('',(18.816852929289,-2.22201809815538,3.94728368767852));
#576=CARTESIAN_POINT('',(18.7807313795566,-2.10664266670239,3.89816992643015));
#577=CARTESIAN_POINT('',(18.7146560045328,-1.87120156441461,3.80762962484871));
#578=CARTESIAN_POINT('',(18.6847023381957,-1.751135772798,3.76620328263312));
#579=CARTESIAN_POINT('',(18.6310686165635,-1.50723594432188,3.69155623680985));
#580=CARTESIAN_POINT('',(18.607382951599,-1.38340538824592,3.65832819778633));
#581=CARTESIAN_POINT('',(18.5662902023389,-1.13274848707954,3.60040240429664));
#582=CARTESIAN_POINT('',(18.5488828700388,-1.00592226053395,3.57570431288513));
#583=CARTESIAN_POINT('',(18.5203590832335,-0.750095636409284,3.53510675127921));
#584=CARTESIAN_POINT('',(18.5092462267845,-0.621094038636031,3.51921231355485));
#585=CARTESIAN_POINT('',(18.4933327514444,-0.361866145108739,3.49642035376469));
#586=CARTESIAN_POINT('',(18.488534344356,-0.231639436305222,3.4895259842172));
#587=CARTESIAN_POINT('',(18.4852595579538,0.029070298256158,3.48482282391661));
#588=CARTESIAN_POINT('',(18.4867838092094,0.159553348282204,3.48701493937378));
#589=CARTESIAN_POINT('',(18.4961550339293,0.419823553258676,3.50046190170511));
#590=CARTESIAN_POINT('',(18.5040020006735,0.549610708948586,3.51171673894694));
#591=CARTESIAN_POINT('',(18.5259609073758,0.80694254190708,3.54308577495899));
#592=CARTESIAN_POINT('',(18.5400429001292,0.934494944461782,3.56315762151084));
#593=CARTESIAN_POINT('',(18.5744450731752,1.18704018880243,3.61191640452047));
#594=CARTESIAN_POINT('',(18.5947630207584,1.31203392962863,3.64060025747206));
#595=CARTESIAN_POINT('',(18.6415709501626,1.55843721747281,3.70620913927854));
#596=CARTESIAN_POINT('',(18.6680514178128,1.67985196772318,3.74312146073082));
#597=CARTESIAN_POINT('',(18.7271385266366,1.91841909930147,3.82478752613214));
#598=CARTESIAN_POINT('',(18.7597414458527,2.03557401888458,3.86953650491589));
#599=CARTESIAN_POINT('',(18.8050250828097,2.18133292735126,3.93109317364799));
#600=CARTESIAN_POINT('',(18.8149200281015,2.21228165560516,3.94451222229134));
#601=CARTESIAN_POINT('',(18.8351428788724,2.27376663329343,3.97186769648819));
#602=CARTESIAN_POINT('',(18.845470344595,2.30430326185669,3.9858035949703));
#603=CARTESIAN_POINT('',(18.8560184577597,2.33464513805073,4.));
#604=B_SPLINE_CURVE_WITH_KNOTS('',3,(#574,#575,#576,#577,#578,#579,#580,#581,#582,#583,#584,
#585,#586,#587,#588,#589,#590,#591,#592,#593,#594,#595,#596,#597,#598,#599,#600,#601,#602,#603),
.UNSPECIFIED.,.F.,.F.,(4,2,2,2,2,2,2,2,2,2,2,2,2,2,4),(0.,0.391018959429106,0.78204799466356,
1.17272587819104,1.56338832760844,1.95427386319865,2.34529628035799,2.7363576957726,
3.12741869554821,3.51662144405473,3.90568500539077,4.29415183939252,4.68238327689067,
4.78783981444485,4.89319161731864),.UNSPECIFIED.);
#605=EDGE_CURVE('E259',#91,#214,#604,.T.);
#606=ORIENTED_EDGE('',*,*,#605,.T.);
#607=ORIENTED_EDGE('',*,*,#217,.T.);
#608=ORIENTED_EDGE('',*,*,#268,.T.);
#609=CARTESIAN_POINT('',(-25.8146605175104,3.09891954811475,16.5));
#610=VERTEX_POINT('',#609);
#611=EDGE_CURVE('E297',#610,#261,#567,.T.);
#612=ORIENTED_EDGE('',*,*,#611,.F.);
#613=CARTESIAN_POINT('',(-11.1495280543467,0.,16.5));
#614=DIRECTION('',(0.,0.,-1.));
#615=DIRECTION('',(-1.,0.,0.));
#616=AXIS2_PLACEMENT_3D('',#613,#614,#615);
#617=ELLIPSE('',#616,18.9321461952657,4.89999999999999);
#618=EDGE_CURVE('E303',#569,#610,#617,.T.);
#619=ORIENTED_EDGE('',*,*,#618,.F.);
#620=EDGE_LOOP('',(#571,#572,#573,#606,#607,#608,#612,#619));
#621=FACE_BOUND('',#620,.T.);
#622=ADVANCED_FACE('F243',(#621),#474,.F.);
#623=CARTESIAN_POINT('',(0.,13.,0.));
#624=DIRECTION('',(0.,0.,-1.));
#625=DIRECTION('',(-1.,0.,0.));
#626=AXIS2_PLACEMENT_3D('',#623,#624,#625);
#627=CYLINDRICAL_SURFACE('',#626,2.74999999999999);
#628=CARTESIAN_POINT('',(0.,13.,-2.05858175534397));
#629=DIRECTION('',(-0.0670532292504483,0.703920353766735,-0.707106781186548));
#630=DIRECTION('',(0.0670532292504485,-0.703920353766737,-0.707106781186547));
#631=AXIS2_PLACEMENT_3D('',#628,#629,#630);
#632=ELLIPSE('',#631,3.889087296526,2.74999999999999);
#633=CARTESIAN_POINT('',(-1.46030976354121,15.3302350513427,0.399630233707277));
#634=VERTEX_POINT('',#633);
#635=EDGE_CURVE('E62',#287,#634,#632,.T.);
#636=ORIENTED_EDGE('',*,*,#635,.T.);
#637=CARTESIAN_POINT('',(-1.4603097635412,15.3302350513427,0.399630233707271));
#638=CARTESIAN_POINT('',(-1.4096226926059,15.3619977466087,0.426443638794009));
#639=CARTESIAN_POINT('',(-1.35744698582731,15.3923914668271,0.452031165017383));
#640=CARTESIAN_POINT('',(-1.25020272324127,15.4501453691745,0.500544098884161));
#641=CARTESIAN_POINT('',(-1.19513207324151,15.477503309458,0.523467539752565));
#642=CARTESIAN_POINT('',(-1.02546482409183,15.5546734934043,0.588004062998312));
#643=CARTESIAN_POINT('',(-0.906733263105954,15.5993782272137,0.625211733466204));
#644=CARTESIAN_POINT('',(-0.660435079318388,15.6726217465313,0.68603223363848));
#645=CARTESIAN_POINT('',(-0.532831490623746,15.7010877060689,0.709583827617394));
#646=CARTESIAN_POINT('',(-0.273252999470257,15.7395214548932,0.741356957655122));
#647=CARTESIAN_POINT('',(-0.141289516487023,15.7495341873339,0.74961573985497));
#648=CARTESIAN_POINT('',(0.11312671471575,15.7504017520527,0.750331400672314));
#649=CARTESIAN_POINT('',(0.235575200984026,15.7425931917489,0.74389074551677));
#650=CARTESIAN_POINT('',(0.477035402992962,15.7110465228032,0.717820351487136));
#651=CARTESIAN_POINT('',(0.596044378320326,15.6872960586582,0.698180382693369));
#652=CARTESIAN_POINT('',(0.826311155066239,15.6256038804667,0.647007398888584));
#653=CARTESIAN_POINT('',(0.937631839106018,15.5877990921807,0.615589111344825));
#654=CARTESIAN_POINT('',(1.15152820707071,15.4999715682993,0.542300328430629));
#655=CARTESIAN_POINT('',(1.25410733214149,15.4499536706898,0.500433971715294));
#656=CARTESIAN_POINT('',(1.46048278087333,15.3334724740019,0.402449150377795));
#657=CARTESIAN_POINT('',(1.56306555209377,15.2657801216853,0.345246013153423));
#658=CARTESIAN_POINT('',(1.75515088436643,15.1204984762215,0.22167216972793));
#659=CARTESIAN_POINT('',(1.84461756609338,15.0428830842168,0.155277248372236));
#660=CARTESIAN_POINT('',(2.0527473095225,14.8383657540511,-0.0209748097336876));
#661=CARTESIAN_POINT('',(2.16273334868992,14.7066591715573,-0.135611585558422));
#662=CARTESIAN_POINT('',(2.30494937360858,14.502193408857,-0.315887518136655));
#663=CARTESIAN_POINT('',(2.34848317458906,14.4330619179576,-0.377208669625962));
#664=CARTESIAN_POINT('',(2.4283637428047,14.2930587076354,-0.502209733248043));
#665=CARTESIAN_POINT('',(2.46472314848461,14.2221903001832,-0.565885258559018));
#666=CARTESIAN_POINT('',(2.49769850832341,14.1506529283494,-0.630606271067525));
#667=B_SPLINE_CURVE_WITH_KNOTS('',3,(#637,#638,#639,#640,#641,#642,#643,#644,#645,#646,#647,
#648,#649,#650,#651,#652,#653,#654,#655,#656,#657,#658,#659,#660,#661,#662,#663,#664,#665,#666),
.UNSPECIFIED.,.F.,.F.,(4,2,2,2,2,2,2,2,2,2,2,2,2,2,4),(0.,0.196574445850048,0.393293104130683,
0.787966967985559,1.18439718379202,1.57986060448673,1.94664647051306,2.31371693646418,
2.67730110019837,3.04074147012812,3.44592744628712,3.85220192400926,4.46760677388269,
4.77383755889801,5.0795239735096),.UNSPECIFIED.);
#668=EDGE_CURVE('E289',#634,#285,#667,.T.);
#669=ORIENTED_EDGE('',*,*,#668,.T.);
#670=ORIENTED_EDGE('',*,*,#288,.T.);
#671=EDGE_LOOP('',(#636,#669,#670));
#672=FACE_BOUND('',#671,.T.);
#673=ORIENTED_EDGE('',*,*,#248,.F.);
#674=EDGE_LOOP('',(#673));
#675=FACE_BOUND('',#674,.T.);
#676=ADVANCED_FACE('F248',(#672,#675),#627,.F.);
#677=CARTESIAN_POINT('',(0.,-13.,0.));
#678=DIRECTION('',(0.,0.,-1.));
#679=DIRECTION('',(-1.,0.,0.));
#680=AXIS2_PLACEMENT_3D('',#677,#678,#679);
#681=CYLINDRICAL_SURFACE('',#680,2.74999999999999);
#682=CARTESIAN_POINT('',(2.02282046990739,-14.8629807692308,0.));
#683=CARTESIAN_POINT('',(1.97797262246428,-14.9116658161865,0.0421943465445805));
#684=CARTESIAN_POINT('',(1.93090292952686,-14.959253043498,0.0832577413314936));
#685=CARTESIAN_POINT('',(1.83219287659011,-15.0518702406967,0.162872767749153));
#686=CARTESIAN_POINT('',(1.78054699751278,-15.0968970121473,0.201421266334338));
#687=CARTESIAN_POINT('',(1.6181859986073,-15.2278536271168,0.313139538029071));
#688=CARTESIAN_POINT('',(1.50049619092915,-15.3091623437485,0.381952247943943));
#689=CARTESIAN_POINT('',(1.26716309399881,-15.4437887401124,0.49528103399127));
#690=CARTESIAN_POINT('',(1.15390896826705,-15.4994806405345,0.541898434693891));
#691=CARTESIAN_POINT('',(0.917073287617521,-15.5957163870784,0.622187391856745));
#692=CARTESIAN_POINT('',(0.793517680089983,-15.6362969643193,0.655890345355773));
#693=CARTESIAN_POINT('',(0.538030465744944,-15.7000857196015,0.708769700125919));
#694=CARTESIAN_POINT('',(0.406048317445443,-15.7231757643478,0.727847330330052));
#695=CARTESIAN_POINT('',(0.138792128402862,-15.7497712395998,0.749815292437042));
#696=CARTESIAN_POINT('',(0.00351930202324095,-15.7532837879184,0.752711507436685));
#697=CARTESIAN_POINT('',(-0.251730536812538,-15.7411289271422,0.742676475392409));
#698=CARTESIAN_POINT('',(-0.371868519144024,-15.7273689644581,0.731319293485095));
#699=CARTESIAN_POINT('',(-0.607638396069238,-15.6847070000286,0.69602469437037));
#700=CARTESIAN_POINT('',(-0.723264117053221,-15.6557849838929,0.672070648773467));
#701=CARTESIAN_POINT('',(-0.948893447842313,-15.583861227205,0.612296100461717));
#702=CARTESIAN_POINT('',(-1.05878203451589,-15.5406480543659,0.576297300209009));
#703=CARTESIAN_POINT('',(-1.2162177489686,-15.4671182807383,0.514766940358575));
#704=CARTESIAN_POINT('',(-1.26740820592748,-15.4411918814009,0.493031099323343));
#705=CARTESIAN_POINT('',(-1.3672470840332,-15.386705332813,0.447244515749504));
#706=CARTESIAN_POINT('',(-1.41589703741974,-15.3581468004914,0.423195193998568));
#707=CARTESIAN_POINT('',(-1.46324400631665,-15.3283936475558,0.398075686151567));
#708=B_SPLINE_CURVE_WITH_KNOTS('',3,(#682,#683,#684,#685,#686,#687,#688,#689,#690,#691,#692,
#693,#694,#695,#696,#697,#698,#699,#700,#701,#702,#703,#704,#705,#706,#707),.UNSPECIFIED.,.F.,
.F.,(4,2,2,2,2,2,2,2,2,2,2,2,4),(0.,0.235392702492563,0.471073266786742,0.944797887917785,
1.34678191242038,1.74778235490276,2.15146763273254,2.55500613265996,2.91765391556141,
3.28078161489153,3.64954178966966,3.83349449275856,4.01733493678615),.UNSPECIFIED.);
#709=CARTESIAN_POINT('',(-1.46030976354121,-15.3302350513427,0.399630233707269));
#710=VERTEX_POINT('',#709);
#711=EDGE_CURVE('E282',#296,#710,#708,.T.);
#712=ORIENTED_EDGE('',*,*,#711,.T.);
#713=CARTESIAN_POINT('',(0.,-13.,-2.05858175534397));
#714=DIRECTION('',(-0.0670532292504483,-0.703920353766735,-0.707106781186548));
#715=DIRECTION('',(0.0670532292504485,0.703920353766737,-0.707106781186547));
#716=AXIS2_PLACEMENT_3D('',#713,#714,#715);
#717=ELLIPSE('',#716,3.889087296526,2.74999999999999);
#718=EDGE_CURVE('E376',#710,#305,#717,.T.);
#719=ORIENTED_EDGE('',*,*,#718,.T.);
#720=ORIENTED_EDGE('',*,*,#306,.T.);
#721=EDGE_LOOP('',(#712,#719,#720));
#722=FACE_BOUND('',#721,.T.);
#723=ORIENTED_EDGE('',*,*,#31,.F.);
#724=EDGE_LOOP('',(#723));
#725=FACE_BOUND('',#724,.T.);
#726=ADVANCED_FACE('F414',(#722,#725),#681,.F.);
#727=CARTESIAN_POINT('',(-1.42241379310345,14.9324056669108,0.));
#728=DIRECTION('',(-0.0670532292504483,0.703920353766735,-0.707106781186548));
#729=DIRECTION('',(0.,0.708701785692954,0.705508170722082));
#730=AXIS2_PLACEMENT_3D('',#727,#728,#729);
#731=PLANE('',#730);
#732=DIRECTION('',(0.0670532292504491,-0.703920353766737,-0.707106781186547));
#733=VECTOR('',#732,1.);
#734=CARTESIAN_POINT('',(-59.2801724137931,13.4391651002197,4.));
#735=LINE('',#734,#733);
#736=EDGE_CURVE('E205',#378,#322,#735,.T.);
#737=ORIENTED_EDGE('',*,*,#736,.F.);
#738=ORIENTED_EDGE('',*,*,#379,.F.);
#739=DIRECTION('',(-0.0670532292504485,0.703920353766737,0.707106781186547));
#740=VECTOR('',#739,1.);
#741=CARTESIAN_POINT('',(-1.42241379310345,14.9324056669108,0.));
#742=LINE('',#741,#740);
#743=EDGE_CURVE('E208',#634,#225,#742,.T.);
#744=ORIENTED_EDGE('',*,*,#743,.F.);
#745=ORIENTED_EDGE('',*,*,#635,.F.);
#746=ORIENTED_EDGE('',*,*,#329,.F.);
#747=EDGE_LOOP('',(#737,#738,#744,#745,#746));
#748=FACE_BOUND('',#747,.T.);
#749=ADVANCED_FACE('F276',(#748),#731,.T.);
#750=CARTESIAN_POINT('',(0.,0.,4.));
#751=DIRECTION('',(0.,0.,1.));
#752=DIRECTION('',(1.,0.,0.));
#753=AXIS2_PLACEMENT_3D('',#750,#751,#752);
#754=CONICAL_SURFACE('',#753,19.,0.78539816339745);
#755=ORIENTED_EDGE('',*,*,#605,.F.);
#756=ORIENTED_EDGE('',*,*,#92,.F.);
#757=DIRECTION('',(-0.0670532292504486,-0.703920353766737,0.707106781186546));
#758=VECTOR('',#757,1.);
#759=CARTESIAN_POINT('',(-1.42241379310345,-14.9324056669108,0.));
#760=LINE('',#759,#758);
#761=EDGE_CURVE('E203',#710,#82,#760,.T.);
#762=ORIENTED_EDGE('',*,*,#761,.F.);
#763=ORIENTED_EDGE('',*,*,#711,.F.);
#764=ORIENTED_EDGE('',*,*,#297,.F.);
#765=ORIENTED_EDGE('',*,*,#668,.F.);
#766=ORIENTED_EDGE('',*,*,#743,.T.);
#767=ORIENTED_EDGE('',*,*,#226,.F.);
#768=EDGE_LOOP('',(#755,#756,#762,#763,#764,#765,#766,#767));
#769=FACE_BOUND('',#768,.T.);
#770=ADVANCED_FACE('F270',(#769),#754,.T.);
#771=CARTESIAN_POINT('',(-58.,0.,0.));
#772=DIRECTION('',(0.,0.,1.));
#773=DIRECTION('',(1.,0.,0.));
#774=AXIS2_PLACEMENT_3D('',#771,#772,#773);
#775=CONICAL_SURFACE('',#774,9.49999999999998,0.78539816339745);
#776=ORIENTED_EDGE('',*,*,#736,.T.);
#777=ORIENTED_EDGE('',*,*,#323,.F.);
#778=DIRECTION('',(0.0670532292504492,0.703920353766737,-0.707106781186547));
#779=VECTOR('',#778,1.);
#780=CARTESIAN_POINT('',(-59.2801724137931,-13.4391651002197,4.));
#781=LINE('',#780,#779);
#782=EDGE_CURVE('E200',#402,#313,#781,.T.);
#783=ORIENTED_EDGE('',*,*,#782,.F.);
#784=ORIENTED_EDGE('',*,*,#418,.F.);
#785=EDGE_LOOP('',(#776,#777,#783,#784));
#786=FACE_BOUND('',#785,.T.);
#787=ADVANCED_FACE('F275',(#786),#775,.T.);
#788=CARTESIAN_POINT('',(-1.42241379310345,-14.9324056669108,0.));
#789=DIRECTION('',(-0.0670532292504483,-0.703920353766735,-0.707106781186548));
#790=DIRECTION('',(0.,0.708701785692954,-0.705508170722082));
#791=AXIS2_PLACEMENT_3D('',#788,#789,#790);
#792=PLANE('',#791);
#793=ORIENTED_EDGE('',*,*,#761,.T.);
#794=ORIENTED_EDGE('',*,*,#441,.F.);
#795=ORIENTED_EDGE('',*,*,#782,.T.);
#796=ORIENTED_EDGE('',*,*,#314,.F.);
#797=ORIENTED_EDGE('',*,*,#718,.F.);
#798=EDGE_LOOP('',(#793,#794,#795,#796,#797));
#799=FACE_BOUND('',#798,.T.);
#800=ADVANCED_FACE('F324',(#799),#792,.T.);
#801=CARTESIAN_POINT('',(0.,0.,0.));
#802=DIRECTION('',(0.,0.,-1.));
#803=DIRECTION('',(-1.,0.,0.));
#804=AXIS2_PLACEMENT_3D('',#801,#802,#803);
#805=CYLINDRICAL_SURFACE('',#804,26.);
#806=ORIENTED_EDGE('',*,*,#451,.T.);
#807=ORIENTED_EDGE('',*,*,#52,.F.);
#808=ORIENTED_EDGE('',*,*,#570,.T.);
#809=CARTESIAN_POINT('',(0.,0.,16.5));
#810=DIRECTION('',(0.,0.,-1.));
#811=DIRECTION('',(-1.,0.,0.));
#812=AXIS2_PLACEMENT_3D('',#809,#810,#811);
#813=CIRCLE('',#812,26.);
#814=EDGE_CURVE('E174',#450,#569,#813,.T.);
#815=ORIENTED_EDGE('',*,*,#814,.F.);
#816=EDGE_LOOP('',(#806,#807,#808,#815));
#817=FACE_BOUND('',#816,.T.);
#818=ADVANCED_FACE('F312',(#817),#805,.T.);
#819=CARTESIAN_POINT('',(-55.5,0.,11.5));
#820=DIRECTION('',(0.,0.,-1.));
#821=DIRECTION('',(-1.,0.,0.));
#822=AXIS2_PLACEMENT_3D('',#819,#820,#821);
#823=PLANE('',#822);
#824=CARTESIAN_POINT('',(-67.5,0.,11.5));
#825=DIRECTION('',(0.,0.,1.));
#826=DIRECTION('',(1.,0.,0.));
#827=AXIS2_PLACEMENT_3D('',#824,#825,#826);
#828=CIRCLE('',#827,3.04999999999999);
#829=CARTESIAN_POINT('',(-64.45,0.,11.5));
#830=VERTEX_POINT('',#829);
#831=EDGE_CURVE('E163',#830,#830,#828,.T.);
#832=ORIENTED_EDGE('',*,*,#831,.F.);
#833=EDGE_LOOP('',(#832));
#834=FACE_BOUND('',#833,.T.);
#835=ORIENTED_EDGE('',*,*,#347,.T.);
#836=ORIENTED_EDGE('',*,*,#410,.T.);
#837=ORIENTED_EDGE('',*,*,#434,.T.);
#838=CARTESIAN_POINT('',(0.,0.,11.5));
#839=DIRECTION('',(0.,0.,-1.));
#840=DIRECTION('',(-1.,0.,0.));
#841=AXIS2_PLACEMENT_3D('',#838,#839,#840);
#842=CIRCLE('',#841,55.5);
#843=EDGE_CURVE('E179',#433,#344,#842,.T.);
#844=ORIENTED_EDGE('',*,*,#843,.T.);
#845=EDGE_LOOP('',(#835,#836,#837,#844));
#846=FACE_BOUND('',#845,.T.);
#847=ADVANCED_FACE('F320',(#834,#846),#823,.F.);
#848=CARTESIAN_POINT('',(0.,0.,0.));
#849=DIRECTION('',(0.,0.,-1.));
#850=DIRECTION('',(-1.,0.,0.));
#851=AXIS2_PLACEMENT_3D('',#848,#849,#850);
#852=CYLINDRICAL_SURFACE('',#851,55.5);
#853=ORIENTED_EDGE('',*,*,#355,.T.);
#854=ORIENTED_EDGE('',*,*,#843,.F.);
#855=ORIENTED_EDGE('',*,*,#465,.T.);
#856=CARTESIAN_POINT('',(0.,0.,16.5));
#857=DIRECTION('',(0.,0.,-1.));
#858=DIRECTION('',(-1.,0.,0.));
#859=AXIS2_PLACEMENT_3D('',#856,#857,#858);
#860=CIRCLE('',#859,55.5);
#861=EDGE_CURVE('E176',#458,#354,#860,.T.);
#862=ORIENTED_EDGE('',*,*,#861,.T.);
#863=EDGE_LOOP('',(#853,#854,#855,#862));
#864=FACE_BOUND('',#863,.T.);
#865=ADVANCED_FACE('F316',(#864),#852,.T.);
#866=CARTESIAN_POINT('',(-26.,0.,16.5));
#867=DIRECTION('',(0.,0.,-1.));
#868=DIRECTION('',(-1.,0.,0.));
#869=AXIS2_PLACEMENT_3D('',#866,#867,#868);
#870=PLANE('',#869);
#871=ORIENTED_EDGE('',*,*,#363,.T.);
#872=ORIENTED_EDGE('',*,*,#861,.F.);
#873=ORIENTED_EDGE('',*,*,#459,.T.);
#874=ORIENTED_EDGE('',*,*,#814,.T.);
#875=ORIENTED_EDGE('',*,*,#618,.T.);
#876=EDGE_CURVE('E54',#610,#362,#813,.T.);
#877=ORIENTED_EDGE('',*,*,#876,.T.);
#878=EDGE_LOOP('',(#871,#872,#873,#874,#875,#877));
#879=FACE_BOUND('',#878,.T.);
#880=ADVANCED_FACE('F311',(#879),#870,.F.);
#881=ORIENTED_EDGE('',*,*,#369,.T.);
#882=ORIENTED_EDGE('',*,*,#876,.F.);
#883=ORIENTED_EDGE('',*,*,#611,.T.);
#884=ORIENTED_EDGE('',*,*,#262,.F.);
#885=EDGE_LOOP('',(#881,#882,#883,#884));
#886=FACE_BOUND('',#885,.T.);
#887=ADVANCED_FACE('F305',(#886),#805,.T.);
#888=CARTESIAN_POINT('',(-67.5,0.,8.5));
#889=DIRECTION('',(0.,0.,1.));
#890=DIRECTION('',(1.,0.,0.));
#891=AXIS2_PLACEMENT_3D('',#888,#889,#890);
#892=CYLINDRICAL_SURFACE('',#891,3.04999999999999);
#893=CARTESIAN_POINT('',(-67.5,0.,8.5));
#894=DIRECTION('',(0.,0.,1.));
#895=DIRECTION('',(1.,0.,0.));
#896=AXIS2_PLACEMENT_3D('',#893,#894,#895);
#897=CIRCLE('',#896,3.04999999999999);
#898=CARTESIAN_POINT('',(-64.45,0.,8.5));
#899=VERTEX_POINT('',#898);
#900=EDGE_CURVE('E167',#899,#899,#897,.T.);
#901=ORIENTED_EDGE('',*,*,#900,.F.);
#902=EDGE_LOOP('',(#901));
#903=FACE_BOUND('',#902,.T.);
#904=ORIENTED_EDGE('',*,*,#831,.T.);
#905=EDGE_LOOP('',(#904));
#906=FACE_BOUND('',#905,.T.);
#907=ADVANCED_FACE('F310',(#903,#906),#892,.F.);
#908=CARTESIAN_POINT('',(-67.5,0.,8.5));
#909=DIRECTION('',(0.,0.,1.));
#910=DIRECTION('',(1.,0.,0.));
#911=AXIS2_PLACEMENT_3D('',#908,#909,#910);
#912=PLANE('',#911);
#913=CARTESIAN_POINT('',(-67.5,0.,8.5));
#914=DIRECTION('',(0.,0.,1.));
#915=DIRECTION('',(1.,0.,0.));
#916=AXIS2_PLACEMENT_3D('',#913,#914,#915);
#917=CIRCLE('',#916,3.);
#918=CARTESIAN_POINT('',(-64.5,0.,8.5));
#919=VERTEX_POINT('',#918);
#920=EDGE_CURVE('E164',#919,#919,#917,.T.);
#921=ORIENTED_EDGE('',*,*,#920,.F.);
#922=EDGE_LOOP('',(#921));
#923=FACE_BOUND('',#922,.T.);
#924=ORIENTED_EDGE('',*,*,#900,.T.);
#925=EDGE_LOOP('',(#924));
#926=FACE_BOUND('',#925,.T.);
#927=ADVANCED_FACE('F157',(#923,#926),#912,.T.);
#928=CARTESIAN_POINT('',(-67.5,0.,8.496));
#929=DIRECTION('',(0.,0.,1.));
#930=DIRECTION('',(1.,0.,0.));
#931=AXIS2_PLACEMENT_3D('',#928,#929,#930);
#932=CONICAL_SURFACE('',#931,3.,1.0471975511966);
#933=CARTESIAN_POINT('',(-67.5,0.,6.76394919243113));
#934=VERTEX_POINT('',#933);
#935=VERTEX_LOOP('',#934);
#936=FACE_BOUND('',#935,.T.);
#937=CARTESIAN_POINT('',(-67.5,0.,8.496));
#938=DIRECTION('',(0.,0.,1.));
#939=DIRECTION('',(1.,0.,0.));
#940=AXIS2_PLACEMENT_3D('',#937,#938,#939);
#941=CIRCLE('',#940,3.);
#942=CARTESIAN_POINT('',(-64.5,0.,8.496));
#943=VERTEX_POINT('',#942);
#944=EDGE_CURVE('E161',#943,#943,#941,.T.);
#945=ORIENTED_EDGE('',*,*,#944,.T.);
#946=EDGE_LOOP('',(#945));
#947=FACE_BOUND('',#946,.T.);
#948=ADVANCED_FACE('F153',(#936,#947),#932,.F.);
#949=CARTESIAN_POINT('',(-67.5,0.,8.5));
#950=DIRECTION('',(0.,0.,1.));
#951=DIRECTION('',(1.,0.,0.));
#952=AXIS2_PLACEMENT_3D('',#949,#950,#951);
#953=CYLINDRICAL_SURFACE('',#952,3.);
#954=ORIENTED_EDGE('',*,*,#944,.F.);
#955=EDGE_LOOP('',(#954));
#956=FACE_BOUND('',#955,.T.);
#957=ORIENTED_EDGE('',*,*,#920,.T.);
#958=EDGE_LOOP('',(#957));
#959=FACE_BOUND('',#958,.T.);
#960=ADVANCED_FACE('F156',(#956,#959),#953,.F.);
#961=CLOSED_SHELL('',(#71,#212,#240,#273,#333,#389,#422,#469,#622,#676,#726,#749,#770,#787,#800,
#818,#847,#865,#880,#887,#907,#927,#948,#960));
#962=MANIFOLD_SOLID_BREP('B2',#961);
#963=ADVANCED_BREP_SHAPE_REPRESENTATION('',(#18,#962),#14);
#964=SHAPE_DEFINITION_REPRESENTATION(#9,#963);
ENDSEC;
END-ISO-10303-21;
